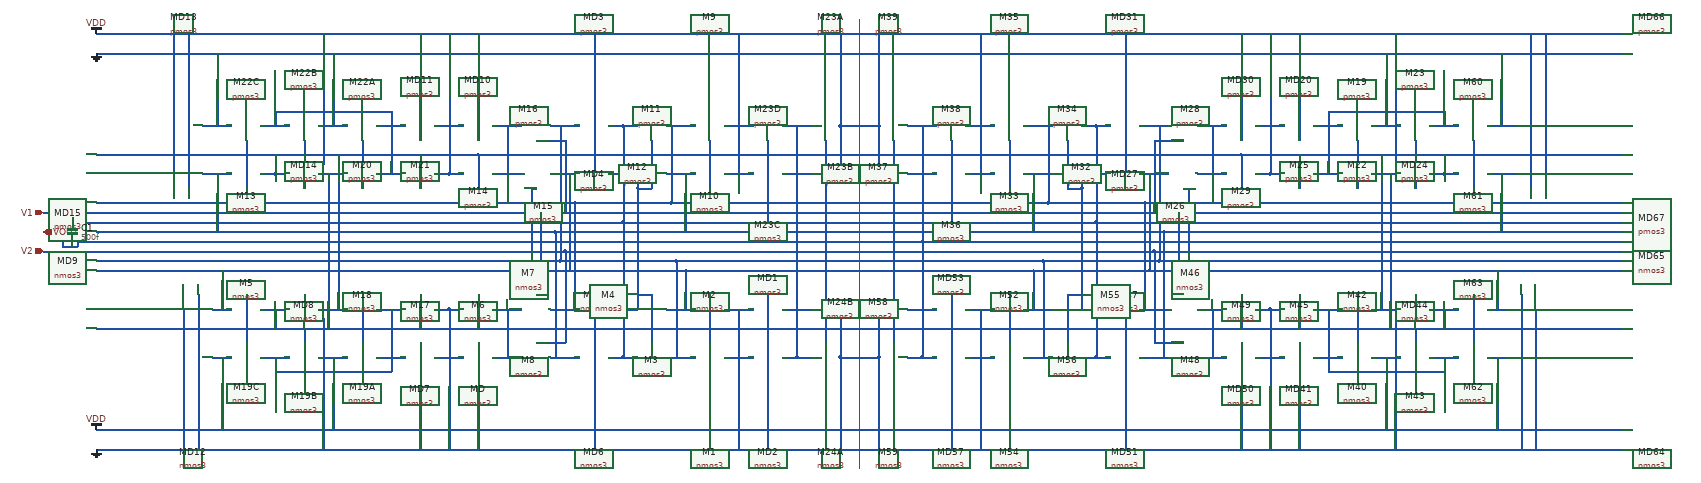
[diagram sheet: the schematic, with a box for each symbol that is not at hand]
v {xschem version=2.9.9 file_version=1.2 }
G {}
K {}
V {}
S {}
E {}
L 4 790 -520 790 410 {}
N -160 80 -150 80 { lab=#net1}
N 750 -300 750 -200 { lab=VDD}
N 630 -300 690 -300 { lab=VOUT}
N 600 -270 600 -170 { lab=#net2}
N 720 -270 720 -170 { lab=#net2}
N 660 -60 790 -60 { lab=VOUT}
N 660 80 690 80 { lab=VOUT}
N 660 180 690 180 { lab=VOUT}
N 750 80 750 180 { lab=GND}
N 720 50 720 150 { lab=#net2}
N 720 -170 720 50 { lab=#net2}
N 750 -490 750 -300 { lab=VDD}
N 540 -490 540 -200 { lab=VDD}
N 510 -200 570 -200 { lab=VDD}
N 510 -300 540 -300 { lab=VDD}
N 540 -300 570 -300 { lab=VDD}
N 390 -300 450 -300 { lab=#net3}
N 390 -200 450 -200 { lab=#net4}
N 360 -270 360 -170 { lab=#net5}
N 600 -170 600 -100 { lab=#net2}
N 300 -300 330 -300 { lab=#net2}
N 300 -300 300 -100 { lab=#net2}
N 300 -100 720 -100 { lab=#net2}
N 330 -200 330 -170 { lab=#net5}
N 330 -170 360 -170 { lab=#net5}
N 300 -100 300 180 { lab=#net2}
N 300 180 330 180 { lab=#net2}
N 510 80 570 80 { lab=GND}
N 540 80 540 370 { lab=GND}
N 330 -170 330 80 { lab=#net5}
N 330 50 360 50 { lab=#net5}
N 390 180 450 180 { lab=#net6}
N 390 80 450 80 { lab=#net7}
N 720 -100 790 -100 { lab=#net2}
N 270 180 300 180 { lab=#net2}
N 270 80 330 80 { lab=#net5}
N 270 -200 330 -200 { lab=#net5}
N 270 -300 300 -300 { lab=#net2}
N 480 50 480 150 { lab=#net8}
N 360 50 360 150 { lab=#net5}
N 630 80 660 80 { lab=VOUT}
N 630 180 660 180 { lab=VOUT}
N 510 180 540 180 { lab=GND}
N 540 180 570 180 { lab=GND}
N 180 -40 790 -40 { lab=V2}
N 120 150 180 150 { lab=V2}
N -790 -120 120 -120 { lab=#net9}
N -790 -40 180 -40 { lab=V2}
N 150 80 210 80 { lab=#net3}
N 150 180 210 180 { lab=#net4}
N 30 80 90 80 { lab=#net10}
N 30 180 90 180 { lab=#net10}
N 60 80 60 180 { lab=#net10}
N 660 -60 660 180 { lab=VOUT}
N 660 -300 660 -60 { lab=VOUT}
N 630 -200 660 -200 { lab=VOUT}
N 660 -200 690 -200 { lab=VOUT}
N 120 -120 790 -120 { lab=#net9}
N 200 -140 400 -140 { lab=#net3}
N 400 -300 400 -140 { lab=#net3}
N -790 -60 660 -60 { lab=VOUT}
N -790 -100 300 -100 { lab=#net2}
N 400 -140 790 -140 { lab=#net3}
N 160 -80 790 -80 { lab=#net4}
N -790 -80 160 -80 { lab=#net4}
N 430 -200 430 -80 { lab=#net4}
N 480 120 790 120 { lab=#net8}
N -790 120 480 120 { lab=#net8}
N 600 50 600 370 { lab=GND}
N 240 50 240 370 { lab=GND}
N 180 -40 180 150 { lab=V2}
N -90 180 -60 180 { lab=GND}
N -60 180 -30 180 { lab=GND}
N 0 50 0 120 { lab=#net8}
N -90 80 -60 80 { lab=GND}
N -60 80 -30 80 { lab=GND}
N -60 80 -60 370 { lab=GND}
N -120 50 -120 120 { lab=#net8}
N -210 80 -160 80 { lab=#net1}
N -180 80 -180 180 { lab=#net1}
N -210 180 -150 180 { lab=#net1}
N -240 120 -240 150 { lab=#net8}
N -240 50 -240 120 { lab=#net8}
N -330 180 -270 180 { lab=VDD}
N -550 180 -510 180 { lab=VDD}
N -450 180 -390 180 { lab=#net1}
N -480 120 -480 150 { lab=#net8}
N -360 120 -360 150 { lab=#net8}
N -330 80 -270 80 { lab=#net11}
N -450 80 -390 80 { lab=#net8}
N -420 80 -420 120 { lab=#net8}
N 150 -300 210 -300 { lab=#net6}
N 150 -200 210 -200 { lab=#net7}
N 410 -20 410 180 { lab=#net6}
N 170 -300 170 -20 { lab=#net6}
N 170 -20 410 -20 { lab=#net6}
N 410 -20 790 -20 { lab=#net6}
N -790 -20 170 -20 { lab=#net6}
N 430 0 430 80 { lab=#net7}
N 190 0 430 0 { lab=#net7}
N 190 -200 190 0 { lab=#net7}
N 180 -270 180 -120 { lab=#net9}
N 120 -270 180 -270 { lab=#net9}
N 130 -120 130 50 { lab=#net9}
N 120 50 130 50 { lab=#net9}
N 110 -170 110 -40 { lab=V2}
N 110 -170 120 -170 { lab=V2}
N 30 -300 90 -300 { lab=#net12}
N 30 -200 90 -200 { lab=#net12}
N 60 -300 60 -200 { lab=#net12}
N 0 -490 0 -270 { lab=VDD}
N 0 -240 0 -170 { lab=#net11}
N 0 -240 780 -240 { lab=#net11}
N 780 -240 790 -240 { lab=#net11}
N -790 -240 0 -240 { lab=#net11}
N -60 -200 -30 -200 { lab=VDD}
N -90 -200 -60 -200 { lab=VDD}
N -90 -300 -60 -300 { lab=VDD}
N -60 -300 -30 -300 { lab=VDD}
N -60 -490 -60 -200 { lab=VDD}
N -120 -490 -120 -270 { lab=VDD}
N -210 -200 -150 -200 { lab=#net13}
N -180 -300 -180 -200 { lab=#net13}
N -210 -300 -150 -300 { lab=#net13}
N -120 -240 -120 -170 { lab=#net11}
N -330 -300 -270 -300 { lab=GND}
N -240 -270 -240 -240 { lab=#net11}
N -360 -270 -360 -240 { lab=#net11}
N -450 -300 -390 -300 { lab=#net13}
N -300 180 -300 330 { lab=VDD}
N -180 180 -180 210 { lab=#net1}
N -420 210 -180 210 { lab=#net1}
N -420 180 -420 210 { lab=#net1}
N -530 180 -530 330 { lab=VDD}
N -550 80 -510 80 { lab=#net7}
N -300 -450 -300 -300 { lab=GND}
N -180 -330 -180 -300 { lab=#net13}
N -420 -330 -180 -330 { lab=#net13}
N -420 -330 -420 -300 { lab=#net13}
N -570 -300 -510 -300 { lab=GND}
N -540 -450 -540 -300 { lab=GND}
N -480 -270 -480 -240 { lab=#net11}
N -240 -240 -240 -170 { lab=#net11}
N -330 -200 -270 -200 { lab=#net8}
N -450 -200 -420 -200 { lab=#net11}
N -420 -200 -390 -200 { lab=#net11}
N -570 -200 -510 -200 { lab=#net4}
N -600 -490 -600 -170 { lab=VDD}
N -580 50 -580 370 { lab=GND}
N -790 0 190 0 { lab=#net7}
N 430 0 790 0 { lab=#net7}
N -530 0 -530 80 { lab=#net7}
N -610 80 -610 370 { lab=GND}
N -630 -490 -630 -200 { lab=VDD}
N 240 -490 240 -170 { lab=VDD}
N 750 180 750 370 { lab=GND}
N -360 50 -360 100 { lab=GND}
N 480 -270 480 -240 { lab=#net11}
N 480 -240 480 -170 { lab=#net11}
N -120 150 -120 370 { lab=GND}
N -0 150 -0 370 { lab=GND}
N -290 -240 -290 80 { lab=#net11}
N -480 -240 -480 -170 { lab=#net11}
N -420 -240 -420 -200 { lab=#net11}
N -360 -220 -360 -170 { lab=VDD}
N -360 -220 -320 -220 { lab=VDD}
N -320 -490 -320 -220 { lab=VDD}
N -360 100 -320 100 { lab=GND}
N -320 100 -320 370 { lab=GND}
N -310 -200 -310 120 { lab=#net8}
N -480 50 -480 120 { lab=#net8}
N 200 -140 200 80 { lab=#net3}
N 160 -80 160 180 { lab=#net4}
N -540 -200 -540 -80 { lab=#net4}
N -790 -140 200 -140 { lab=#net3}
N -830 -110 -830 -100 { lab=#net2}
N -840 -110 -830 -110 { lab=#net2}
N -830 -60 -830 -50 { lab=VOUT}
N -840 -50 -830 -50 { lab=VOUT}
N -850 -50 -840 -50 { lab=VOUT}
N 1730 80 1740 80 { lab=#net14}
N 830 -300 830 -200 { lab=VDD}
N 890 -300 950 -300 { lab=VOUT}
N 980 -270 980 -170 { lab=#net2}
N 860 -270 860 -170 { lab=#net2}
N 790 -60 920 -60 { lab=VOUT}
N 890 80 920 80 { lab=VOUT}
N 890 180 920 180 { lab=VOUT}
N 830 80 830 180 { lab=GND}
N 860 50 860 150 { lab=#net2}
N 860 -170 860 50 { lab=#net2}
N 830 -490 830 -300 { lab=VDD}
N 1040 -490 1040 -200 { lab=VDD}
N 1010 -200 1070 -200 { lab=VDD}
N 1040 -300 1070 -300 { lab=VDD}
N 1010 -300 1040 -300 { lab=VDD}
N 1130 -300 1190 -300 { lab=#net3}
N 1130 -200 1190 -200 { lab=#net4}
N 1220 -270 1220 -170 { lab=#net15}
N 980 -170 980 -100 { lab=#net2}
N 1250 -300 1280 -300 { lab=#net2}
N 1280 -300 1280 -100 { lab=#net2}
N 860 -100 1280 -100 { lab=#net2}
N 1250 -200 1250 -170 { lab=#net15}
N 1220 -170 1250 -170 { lab=#net15}
N 1280 -100 1280 180 { lab=#net2}
N 1250 180 1280 180 { lab=#net2}
N 1010 80 1070 80 { lab=GND}
N 1040 80 1040 370 { lab=GND}
N 1250 -170 1250 80 { lab=#net15}
N 1220 50 1250 50 { lab=#net15}
N 1130 180 1190 180 { lab=#net6}
N 1130 80 1190 80 { lab=#net7}
N 790 -100 860 -100 { lab=#net2}
N 1280 180 1310 180 { lab=#net2}
N 1250 80 1310 80 { lab=#net15}
N 1250 -200 1310 -200 { lab=#net15}
N 1280 -300 1310 -300 { lab=#net2}
N 1100 50 1100 150 { lab=#net8}
N 1220 50 1220 150 { lab=#net15}
N 920 80 950 80 { lab=VOUT}
N 920 180 950 180 { lab=VOUT}
N 1040 180 1070 180 { lab=GND}
N 1010 180 1040 180 { lab=GND}
N 790 -40 1400 -40 { lab=V2}
N 1400 150 1460 150 { lab=V2}
N 1460 -120 2370 -120 { lab=#net9}
N 1400 -40 2370 -40 { lab=V2}
N 1370 80 1430 80 { lab=#net3}
N 1370 180 1430 180 { lab=#net4}
N 1490 80 1550 80 { lab=#net16}
N 1490 180 1550 180 { lab=#net16}
N 1520 80 1520 180 { lab=#net16}
N 920 -60 920 180 { lab=VOUT}
N 920 -300 920 -60 { lab=VOUT}
N 920 -200 950 -200 { lab=VOUT}
N 890 -200 920 -200 { lab=VOUT}
N 790 -120 1460 -120 { lab=#net9}
N 1180 -140 1380 -140 { lab=#net3}
N 1180 -300 1180 -140 { lab=#net3}
N 920 -60 2370 -60 { lab=VOUT}
N 1280 -100 2370 -100 { lab=#net2}
N 790 -140 1180 -140 { lab=#net3}
N 790 -80 1420 -80 { lab=#net4}
N 1420 -80 2370 -80 { lab=#net4}
N 1150 -200 1150 -80 { lab=#net4}
N 790 120 1100 120 { lab=#net8}
N 1100 120 2370 120 { lab=#net8}
N 980 50 980 370 { lab=GND}
N 1340 50 1340 370 { lab=GND}
N 1400 -40 1400 150 { lab=V2}
N 1640 180 1670 180 { lab=GND}
N 1610 180 1640 180 { lab=GND}
N 1580 50 1580 120 { lab=#net8}
N 1640 80 1670 80 { lab=GND}
N 1610 80 1640 80 { lab=GND}
N 1640 80 1640 370 { lab=GND}
N 1700 50 1700 120 { lab=#net8}
N 1740 80 1790 80 { lab=#net14}
N 1760 80 1760 180 { lab=#net14}
N 1730 180 1790 180 { lab=#net14}
N 1820 120 1820 150 { lab=#net8}
N 1820 50 1820 120 { lab=#net8}
N 1850 180 1910 180 { lab=VDD}
N 2090 180 2130 180 { lab=VDD}
N 1970 180 2030 180 { lab=#net14}
N 2060 120 2060 150 { lab=#net8}
N 1940 120 1940 150 { lab=#net8}
N 1850 80 1910 80 { lab=#net11}
N 1970 80 2030 80 { lab=#net8}
N 2000 80 2000 120 { lab=#net8}
N 1370 -300 1430 -300 { lab=#net6}
N 1370 -200 1430 -200 { lab=#net7}
N 1170 -20 1170 180 { lab=#net6}
N 1410 -300 1410 -20 { lab=#net6}
N 1170 -20 1410 -20 { lab=#net6}
N 790 -20 1170 -20 { lab=#net6}
N 1410 -20 2370 -20 { lab=#net6}
N 1150 0 1150 80 { lab=#net7}
N 1150 0 1390 0 { lab=#net7}
N 1390 -200 1390 0 { lab=#net7}
N 1400 -270 1400 -120 { lab=#net9}
N 1400 -270 1460 -270 { lab=#net9}
N 1450 -120 1450 50 { lab=#net9}
N 1450 50 1460 50 { lab=#net9}
N 1470 -170 1470 -40 { lab=V2}
N 1460 -170 1470 -170 { lab=V2}
N 1490 -300 1550 -300 { lab=#net17}
N 1490 -200 1550 -200 { lab=#net17}
N 1520 -300 1520 -200 { lab=#net17}
N 1580 -490 1580 -270 { lab=VDD}
N 1580 -240 1580 -170 { lab=#net11}
N 800 -240 1580 -240 { lab=#net11}
N 790 -240 800 -240 { lab=#net11}
N 1580 -240 2370 -240 { lab=#net11}
N 1610 -200 1640 -200 { lab=VDD}
N 1640 -200 1670 -200 { lab=VDD}
N 1640 -300 1670 -300 { lab=VDD}
N 1610 -300 1640 -300 { lab=VDD}
N 1640 -490 1640 -200 { lab=VDD}
N 1700 -490 1700 -270 { lab=VDD}
N 1730 -200 1790 -200 { lab=#net18}
N 1760 -300 1760 -200 { lab=#net18}
N 1730 -300 1790 -300 { lab=#net18}
N 1700 -240 1700 -170 { lab=#net11}
N 1850 -300 1910 -300 { lab=GND}
N 1820 -270 1820 -240 { lab=#net11}
N 1940 -270 1940 -240 { lab=#net11}
N 1970 -300 2030 -300 { lab=#net18}
N 1880 180 1880 330 { lab=VDD}
N 1760 180 1760 210 { lab=#net14}
N 1760 210 2000 210 { lab=#net14}
N 2000 180 2000 210 { lab=#net14}
N 2110 180 2110 330 { lab=VDD}
N 2090 80 2130 80 { lab=#net7}
N 1880 -450 1880 -300 { lab=GND}
N 1760 -330 1760 -300 { lab=#net18}
N 1760 -330 2000 -330 { lab=#net18}
N 2000 -330 2000 -300 { lab=#net18}
N 2090 -300 2150 -300 { lab=GND}
N 2120 -450 2120 -300 { lab=GND}
N 2060 -270 2060 -240 { lab=#net11}
N 1820 -240 1820 -170 { lab=#net11}
N 1850 -200 1910 -200 { lab=#net8}
N 2000 -200 2030 -200 { lab=#net11}
N 1970 -200 2000 -200 { lab=#net11}
N 2090 -200 2150 -200 { lab=#net4}
N 2180 -490 2180 -170 { lab=VDD}
N 2160 50 2160 370 { lab=GND}
N 1390 0 2370 0 { lab=#net7}
N 790 0 1150 0 { lab=#net7}
N 2110 0 2110 80 { lab=#net7}
N 2190 80 2190 370 { lab=GND}
N 2210 -490 2210 -200 { lab=VDD}
N 1340 -490 1340 -170 { lab=VDD}
N 830 180 830 370 { lab=GND}
N 1940 50 1940 100 { lab=GND}
N 1100 -270 1100 -240 { lab=#net11}
N 1100 -240 1100 -170 { lab=#net11}
N 1700 150 1700 370 { lab=GND}
N 1580 150 1580 370 { lab=GND}
N 1870 -240 1870 80 { lab=#net11}
N 2060 -240 2060 -170 { lab=#net11}
N 2000 -240 2000 -200 { lab=#net11}
N 1940 -220 1940 -170 { lab=VDD}
N 1900 -220 1940 -220 { lab=VDD}
N 1900 -490 1900 -220 { lab=VDD}
N 1900 100 1940 100 { lab=GND}
N 1900 100 1900 370 { lab=GND}
N 1890 -200 1890 120 { lab=#net8}
N 2060 50 2060 120 { lab=#net8}
N 1380 -140 1380 80 { lab=#net3}
N 1420 -80 1420 180 { lab=#net4}
N 2120 -200 2120 -80 { lab=#net4}
N 1380 -140 2370 -140 { lab=#net3}
N 790 -450 2370 -450 { lab=GND}
N 790 -490 2370 -490 { lab=VDD}
N 790 330 2370 330 { lab=VDD}
N 790 370 2370 370 { lab=GND}
N -790 330 790 330 { lab=VDD}
N -790 370 790 370 { lab=GND}
N -790 -490 790 -490 { lab=VDD}
N -790 -450 790 -450 { lab=GND}
N 750 -300 830 -300 { lab=VDD}
N 750 -200 830 -200 { lab=VDD}
N 750 180 830 180 { lab=GND}
N 750 80 830 80 { lab=GND}
N -830 -100 -790 -100 { lab=#net2}
N -830 -60 -790 -60 { lab=VOUT}
N -860 -50 -850 -50 { lab=VOUT}
N -860 -80 -860 -50 { lab=VOUT}
N -900 -80 -860 -80 { lab=VOUT}
N -900 -40 -790 -40 {}
N -900 -120 -790 -120 {}
C {madvlsi/pmos3.sym} -240 -300 3 0 {name=M22A
L=.6
W=1.5
body=VDD
nf=1
mult=1
ad="'int((nf+1)/2) * W/nf * 0.29'" 
pd="'2*int((nf+1)/2) * (W/nf + 0.29)'"
as="'int((nf+2)/2) * W/nf * 0.29'" 
ps="'2*int((nf+2)/2) * (W/nf + 0.29)'"
nrd="'0.29 / W'" nrs="'0.29 / W'"
sa=0 sb=0 sd=0
model=pfet_01v8
spiceprefix=X
}
C {madvlsi/pmos3.sym} -120 -300 3 0 {name=MD11
L=.6
W=1.5
body=VDD
nf=1
mult=1
ad="'int((nf+1)/2) * W/nf * 0.29'" 
pd="'2*int((nf+1)/2) * (W/nf + 0.29)'"
as="'int((nf+2)/2) * W/nf * 0.29'" 
ps="'2*int((nf+2)/2) * (W/nf + 0.29)'"
nrd="'0.29 / W'" nrs="'0.29 / W'"
sa=0 sb=0 sd=0
model=pfet_01v8
spiceprefix=X
}
C {madvlsi/pmos3.sym} -240 -200 3 0 {name=M20
L=.6
W=1.5
body=VDD
nf=1
mult=1
ad="'int((nf+1)/2) * W/nf * 0.29'" 
pd="'2*int((nf+1)/2) * (W/nf + 0.29)'"
as="'int((nf+2)/2) * W/nf * 0.29'" 
ps="'2*int((nf+2)/2) * (W/nf + 0.29)'"
nrd="'0.29 / W'" nrs="'0.29 / W'"
sa=0 sb=0 sd=0
model=pfet_01v8
spiceprefix=X
}
C {madvlsi/pmos3.sym} -360 -300 3 0 {name=M22B
L=.6
W=1.5
body=VDD
nf=1
mult=1
ad="'int((nf+1)/2) * W/nf * 0.29'" 
pd="'2*int((nf+1)/2) * (W/nf + 0.29)'"
as="'int((nf+2)/2) * W/nf * 0.29'" 
ps="'2*int((nf+2)/2) * (W/nf + 0.29)'"
nrd="'0.29 / W'" nrs="'0.29 / W'"
sa=0 sb=0 sd=0
model=pfet_01v8
spiceprefix=X
}
C {madvlsi/pmos3.sym} -360 -200 3 0 {name=MD14
L=.6
W=1.5
body=VDD
nf=1
mult=1
ad="'int((nf+1)/2) * W/nf * 0.29'" 
pd="'2*int((nf+1)/2) * (W/nf + 0.29)'"
as="'int((nf+2)/2) * W/nf * 0.29'" 
ps="'2*int((nf+2)/2) * (W/nf + 0.29)'"
nrd="'0.29 / W'" nrs="'0.29 / W'"
sa=0 sb=0 sd=0
model=pfet_01v8
spiceprefix=X
}
C {madvlsi/pmos3.sym} -120 -200 3 0 {name=M21
L=.6
W=1.5
body=VDD
nf=1
mult=1
ad="'int((nf+1)/2) * W/nf * 0.29'" 
pd="'2*int((nf+1)/2) * (W/nf + 0.29)'"
as="'int((nf+2)/2) * W/nf * 0.29'" 
ps="'2*int((nf+2)/2) * (W/nf + 0.29)'"
nrd="'0.29 / W'" nrs="'0.29 / W'"
sa=0 sb=0 sd=0
model=pfet_01v8
spiceprefix=X
}
C {madvlsi/pmos3.sym} 120 -200 3 0 {name=M15
L=.6
W=1.5
body=VDD
nf=1
mult=1
ad="'int((nf+1)/2) * W/nf * 0.29'" 
pd="'2*int((nf+1)/2) * (W/nf + 0.29)'"
as="'int((nf+2)/2) * W/nf * 0.29'" 
ps="'2*int((nf+2)/2) * (W/nf + 0.29)'"
nrd="'0.29 / W'" nrs="'0.29 / W'"
sa=0 sb=0 sd=0
model=pfet_01v8
spiceprefix=X
}
C {madvlsi/pmos3.sym} 240 -200 3 0 {name=MD4
L=.6
W=1.5
body=VDD
nf=1
mult=1
ad="'int((nf+1)/2) * W/nf * 0.29'" 
pd="'2*int((nf+1)/2) * (W/nf + 0.29)'"
as="'int((nf+2)/2) * W/nf * 0.29'" 
ps="'2*int((nf+2)/2) * (W/nf + 0.29)'"
nrd="'0.29 / W'" nrs="'0.29 / W'"
sa=0 sb=0 sd=0
model=pfet_01v8
spiceprefix=X
}
C {madvlsi/pmos3.sym} 120 -300 3 0 {name=M16
L=.6
W=1.5
body=VDD
nf=1
mult=1
ad="'int((nf+1)/2) * W/nf * 0.29'" 
pd="'2*int((nf+1)/2) * (W/nf + 0.29)'"
as="'int((nf+2)/2) * W/nf * 0.29'" 
ps="'2*int((nf+2)/2) * (W/nf + 0.29)'"
nrd="'0.29 / W'" nrs="'0.29 / W'"
sa=0 sb=0 sd=0
model=pfet_01v8
spiceprefix=X
}
C {madvlsi/pmos3.sym} 0 -200 3 0 {name=M14
L=.6
W=1.5
body=VDD
nf=1
mult=1
ad="'int((nf+1)/2) * W/nf * 0.29'" 
pd="'2*int((nf+1)/2) * (W/nf + 0.29)'"
as="'int((nf+2)/2) * W/nf * 0.29'" 
ps="'2*int((nf+2)/2) * (W/nf + 0.29)'"
nrd="'0.29 / W'" nrs="'0.29 / W'"
sa=0 sb=0 sd=0
model=pfet_01v8
spiceprefix=X
}
C {madvlsi/pmos3.sym} 0 -300 3 0 {name=MD10
L=.6
W=1.5
body=VDD
nf=1
mult=1
ad="'int((nf+1)/2) * W/nf * 0.29'" 
pd="'2*int((nf+1)/2) * (W/nf + 0.29)'"
as="'int((nf+2)/2) * W/nf * 0.29'" 
ps="'2*int((nf+2)/2) * (W/nf + 0.29)'"
nrd="'0.29 / W'" nrs="'0.29 / W'"
sa=0 sb=0 sd=0
model=pfet_01v8
spiceprefix=X
}
C {madvlsi/pmos3.sym} 240 -300 3 0 {name=MD3
L=.6
W=1.5
body=VDD
nf=1
mult=1
ad="'int((nf+1)/2) * W/nf * 0.29'" 
pd="'2*int((nf+1)/2) * (W/nf + 0.29)'"
as="'int((nf+2)/2) * W/nf * 0.29'" 
ps="'2*int((nf+2)/2) * (W/nf + 0.29)'"
nrd="'0.29 / W'" nrs="'0.29 / W'"
sa=0 sb=0 sd=0
model=pfet_01v8
spiceprefix=X
}
C {madvlsi/pmos3.sym} 360 -200 3 0 {name=M12
L=.6
W=1.5
body=VDD
nf=1
mult=1
ad="'int((nf+1)/2) * W/nf * 0.29'" 
pd="'2*int((nf+1)/2) * (W/nf + 0.29)'"
as="'int((nf+2)/2) * W/nf * 0.29'" 
ps="'2*int((nf+2)/2) * (W/nf + 0.29)'"
nrd="'0.29 / W'" nrs="'0.29 / W'"
sa=0 sb=0 sd=0
model=pfet_01v8
spiceprefix=X
}
C {madvlsi/pmos3.sym} 480 -200 3 0 {name=M10
L=.6
W=1.5
body=VDD
nf=1
mult=1
ad="'int((nf+1)/2) * W/nf * 0.29'" 
pd="'2*int((nf+1)/2) * (W/nf + 0.29)'"
as="'int((nf+2)/2) * W/nf * 0.29'" 
ps="'2*int((nf+2)/2) * (W/nf + 0.29)'"
nrd="'0.29 / W'" nrs="'0.29 / W'"
sa=0 sb=0 sd=0
model=pfet_01v8
spiceprefix=X
}
C {madvlsi/pmos3.sym} 360 -300 3 0 {name=M11
L=.6
W=1.5
body=VDD
nf=1
mult=1
ad="'int((nf+1)/2) * W/nf * 0.29'" 
pd="'2*int((nf+1)/2) * (W/nf + 0.29)'"
as="'int((nf+2)/2) * W/nf * 0.29'" 
ps="'2*int((nf+2)/2) * (W/nf + 0.29)'"
nrd="'0.29 / W'" nrs="'0.29 / W'"
sa=0 sb=0 sd=0
model=pfet_01v8
spiceprefix=X
}
C {madvlsi/pmos3.sym} 480 -300 3 0 {name=M9
L=.6
W=1.5
body=VDD
nf=1
mult=1
ad="'int((nf+1)/2) * W/nf * 0.29'" 
pd="'2*int((nf+1)/2) * (W/nf + 0.29)'"
as="'int((nf+2)/2) * W/nf * 0.29'" 
ps="'2*int((nf+2)/2) * (W/nf + 0.29)'"
nrd="'0.29 / W'" nrs="'0.29 / W'"
sa=0 sb=0 sd=0
model=pfet_01v8
spiceprefix=X
}
C {madvlsi/pmos3.sym} 600 -200 3 0 {name=M23C
L=.6
W=1.5
body=VDD
nf=1
mult=1
ad="'int((nf+1)/2) * W/nf * 0.29'" 
pd="'2*int((nf+1)/2) * (W/nf + 0.29)'"
as="'int((nf+2)/2) * W/nf * 0.29'" 
ps="'2*int((nf+2)/2) * (W/nf + 0.29)'"
nrd="'0.29 / W'" nrs="'0.29 / W'"
sa=0 sb=0 sd=0
model=pfet_01v8
spiceprefix=X
}
C {madvlsi/pmos3.sym} 720 -200 3 0 {name=M23B
L=.6
W=1.5
body=VDD
nf=1
mult=1
ad="'int((nf+1)/2) * W/nf * 0.29'" 
pd="'2*int((nf+1)/2) * (W/nf + 0.29)'"
as="'int((nf+2)/2) * W/nf * 0.29'" 
ps="'2*int((nf+2)/2) * (W/nf + 0.29)'"
nrd="'0.29 / W'" nrs="'0.29 / W'"
sa=0 sb=0 sd=0
model=pfet_01v8
spiceprefix=X
}
C {madvlsi/pmos3.sym} 600 -300 3 0 {name=M23D
L=.6
W=1.5
body=VDD
nf=1
mult=1
ad="'int((nf+1)/2) * W/nf * 0.29'" 
pd="'2*int((nf+1)/2) * (W/nf + 0.29)'"
as="'int((nf+2)/2) * W/nf * 0.29'" 
ps="'2*int((nf+2)/2) * (W/nf + 0.29)'"
nrd="'0.29 / W'" nrs="'0.29 / W'"
sa=0 sb=0 sd=0
model=pfet_01v8
spiceprefix=X
}
C {madvlsi/pmos3.sym} 720 -300 3 0 {name=M23A
L=.6
W=1.5
body=VDD
nf=1
mult=1
ad="'int((nf+1)/2) * W/nf * 0.29'" 
pd="'2*int((nf+1)/2) * (W/nf + 0.29)'"
as="'int((nf+2)/2) * W/nf * 0.29'" 
ps="'2*int((nf+2)/2) * (W/nf + 0.29)'"
nrd="'0.29 / W'" nrs="'0.29 / W'"
sa=0 sb=0 sd=0
model=pfet_01v8
spiceprefix=X
}
C {madvlsi/nmos3.sym} -240 180 1 0 {name=M19A
L=.6
W=1.5
body=GND
nf=1
mult=1
ad="'int((nf+1)/2) * W/nf * 0.29'" 
pd="'2*int((nf+1)/2) * (W/nf + 0.29)'"
as="'int((nf+2)/2) * W/nf * 0.29'" 
ps="'2*int((nf+2)/2) * (W/nf + 0.29)'"
nrd="'0.29 / W'" nrs="'0.29 / W'"
sa=0 sb=0 sd=0
model=nfet_01v8
spiceprefix=X
}
C {madvlsi/nmos3.sym} -120 180 1 0 {name=MD7
L=.6
W=1.5
body=GND
nf=1
mult=1
ad="'int((nf+1)/2) * W/nf * 0.29'" 
pd="'2*int((nf+1)/2) * (W/nf + 0.29)'"
as="'int((nf+2)/2) * W/nf * 0.29'" 
ps="'2*int((nf+2)/2) * (W/nf + 0.29)'"
nrd="'0.29 / W'" nrs="'0.29 / W'"
sa=0 sb=0 sd=0
model=nfet_01v8
spiceprefix=X
}
C {madvlsi/nmos3.sym} -240 80 1 0 {name=M18
L=.6
W=1.5
body=GND
nf=1
mult=1
ad="'int((nf+1)/2) * W/nf * 0.29'" 
pd="'2*int((nf+1)/2) * (W/nf + 0.29)'"
as="'int((nf+2)/2) * W/nf * 0.29'" 
ps="'2*int((nf+2)/2) * (W/nf + 0.29)'"
nrd="'0.29 / W'" nrs="'0.29 / W'"
sa=0 sb=0 sd=0
model=nfet_01v8
spiceprefix=X
}
C {madvlsi/nmos3.sym} -360 180 1 0 {name=M19B
L=.6
W=1.5
body=GND
nf=1
mult=1
ad="'int((nf+1)/2) * W/nf * 0.29'" 
pd="'2*int((nf+1)/2) * (W/nf + 0.29)'"
as="'int((nf+2)/2) * W/nf * 0.29'" 
ps="'2*int((nf+2)/2) * (W/nf + 0.29)'"
nrd="'0.29 / W'" nrs="'0.29 / W'"
sa=0 sb=0 sd=0
model=nfet_01v8
spiceprefix=X
}
C {madvlsi/nmos3.sym} -360 80 1 0 {name=MD8
L=.6
W=1.5
body=GND
nf=1
mult=1
ad="'int((nf+1)/2) * W/nf * 0.29'" 
pd="'2*int((nf+1)/2) * (W/nf + 0.29)'"
as="'int((nf+2)/2) * W/nf * 0.29'" 
ps="'2*int((nf+2)/2) * (W/nf + 0.29)'"
nrd="'0.29 / W'" nrs="'0.29 / W'"
sa=0 sb=0 sd=0
model=nfet_01v8
spiceprefix=X
}
C {madvlsi/nmos3.sym} -120 80 1 0 {name=M17
L=.6
W=1.5
body=GND
nf=1
mult=1
ad="'int((nf+1)/2) * W/nf * 0.29'" 
pd="'2*int((nf+1)/2) * (W/nf + 0.29)'"
as="'int((nf+2)/2) * W/nf * 0.29'" 
ps="'2*int((nf+2)/2) * (W/nf + 0.29)'"
nrd="'0.29 / W'" nrs="'0.29 / W'"
sa=0 sb=0 sd=0
model=nfet_01v8
spiceprefix=X
}
C {madvlsi/nmos3.sym} 120 80 1 0 {name=M7
L=.6
W=1.5
body=GND
nf=1
mult=1
ad="'int((nf+1)/2) * W/nf * 0.29'" 
pd="'2*int((nf+1)/2) * (W/nf + 0.29)'"
as="'int((nf+2)/2) * W/nf * 0.29'" 
ps="'2*int((nf+2)/2) * (W/nf + 0.29)'"
nrd="'0.29 / W'" nrs="'0.29 / W'"
sa=0 sb=0 sd=0
model=nfet_01v8
spiceprefix=X
}
C {madvlsi/nmos3.sym} 240 80 1 0 {name=MD5
L=.6
W=1.5
body=GND
nf=1
mult=1
ad="'int((nf+1)/2) * W/nf * 0.29'" 
pd="'2*int((nf+1)/2) * (W/nf + 0.29)'"
as="'int((nf+2)/2) * W/nf * 0.29'" 
ps="'2*int((nf+2)/2) * (W/nf + 0.29)'"
nrd="'0.29 / W'" nrs="'0.29 / W'"
sa=0 sb=0 sd=0
model=nfet_01v8
spiceprefix=X
}
C {madvlsi/nmos3.sym} 120 180 1 0 {name=M8
L=.6
W=1.5
body=GND
nf=1
mult=1
ad="'int((nf+1)/2) * W/nf * 0.29'" 
pd="'2*int((nf+1)/2) * (W/nf + 0.29)'"
as="'int((nf+2)/2) * W/nf * 0.29'" 
ps="'2*int((nf+2)/2) * (W/nf + 0.29)'"
nrd="'0.29 / W'" nrs="'0.29 / W'"
sa=0 sb=0 sd=0
model=nfet_01v8
spiceprefix=X
}
C {madvlsi/nmos3.sym} 0 80 1 0 {name=M6
L=.6
W=1.5
body=GND
nf=1
mult=1
ad="'int((nf+1)/2) * W/nf * 0.29'" 
pd="'2*int((nf+1)/2) * (W/nf + 0.29)'"
as="'int((nf+2)/2) * W/nf * 0.29'" 
ps="'2*int((nf+2)/2) * (W/nf + 0.29)'"
nrd="'0.29 / W'" nrs="'0.29 / W'"
sa=0 sb=0 sd=0
model=nfet_01v8
spiceprefix=X
}
C {madvlsi/nmos3.sym} 0 180 1 0 {name=MD
L=.6
W=1.5
body=GND
nf=1
mult=1
ad="'int((nf+1)/2) * W/nf * 0.29'" 
pd="'2*int((nf+1)/2) * (W/nf + 0.29)'"
as="'int((nf+2)/2) * W/nf * 0.29'" 
ps="'2*int((nf+2)/2) * (W/nf + 0.29)'"
nrd="'0.29 / W'" nrs="'0.29 / W'"
sa=0 sb=0 sd=0
model=nfet_01v8
spiceprefix=X
}
C {madvlsi/nmos3.sym} 240 180 1 0 {name=MD6
L=.6
W=1.5
body=GND
nf=1
mult=1
ad="'int((nf+1)/2) * W/nf * 0.29'" 
pd="'2*int((nf+1)/2) * (W/nf + 0.29)'"
as="'int((nf+2)/2) * W/nf * 0.29'" 
ps="'2*int((nf+2)/2) * (W/nf + 0.29)'"
nrd="'0.29 / W'" nrs="'0.29 / W'"
sa=0 sb=0 sd=0
model=nfet_01v8
spiceprefix=X
}
C {madvlsi/nmos3.sym} 480 80 1 0 {name=M2
L=.6
W=1.5
body=GND
nf=1
mult=1
ad="'int((nf+1)/2) * W/nf * 0.29'" 
pd="'2*int((nf+1)/2) * (W/nf + 0.29)'"
as="'int((nf+2)/2) * W/nf * 0.29'" 
ps="'2*int((nf+2)/2) * (W/nf + 0.29)'"
nrd="'0.29 / W'" nrs="'0.29 / W'"
sa=0 sb=0 sd=0
model=nfet_01v8
spiceprefix=X
}
C {madvlsi/nmos3.sym} 600 80 1 0 {name=MD1
L=.6
W=1.5
body=GND
nf=1
mult=1
ad="'int((nf+1)/2) * W/nf * 0.29'" 
pd="'2*int((nf+1)/2) * (W/nf + 0.29)'"
as="'int((nf+2)/2) * W/nf * 0.29'" 
ps="'2*int((nf+2)/2) * (W/nf + 0.29)'"
nrd="'0.29 / W'" nrs="'0.29 / W'"
sa=0 sb=0 sd=0
model=nfet_01v8
spiceprefix=X
}
C {madvlsi/nmos3.sym} 480 180 1 0 {name=M1
L=.6
W=1.5
body=GND
nf=1
mult=1
ad="'int((nf+1)/2) * W/nf * 0.29'" 
pd="'2*int((nf+1)/2) * (W/nf + 0.29)'"
as="'int((nf+2)/2) * W/nf * 0.29'" 
ps="'2*int((nf+2)/2) * (W/nf + 0.29)'"
nrd="'0.29 / W'" nrs="'0.29 / W'"
sa=0 sb=0 sd=0
model=nfet_01v8
spiceprefix=X
}
C {madvlsi/nmos3.sym} 360 80 1 0 {name=M4
L=.6
W=1.5
body=GND
nf=1
mult=1
ad="'int((nf+1)/2) * W/nf * 0.29'" 
pd="'2*int((nf+1)/2) * (W/nf + 0.29)'"
as="'int((nf+2)/2) * W/nf * 0.29'" 
ps="'2*int((nf+2)/2) * (W/nf + 0.29)'"
nrd="'0.29 / W'" nrs="'0.29 / W'"
sa=0 sb=0 sd=0
model=nfet_01v8
spiceprefix=X
}
C {madvlsi/nmos3.sym} 360 180 1 0 {name=M3
L=.6
W=1.5
body=GND
nf=1
mult=1
ad="'int((nf+1)/2) * W/nf * 0.29'" 
pd="'2*int((nf+1)/2) * (W/nf + 0.29)'"
as="'int((nf+2)/2) * W/nf * 0.29'" 
ps="'2*int((nf+2)/2) * (W/nf + 0.29)'"
nrd="'0.29 / W'" nrs="'0.29 / W'"
sa=0 sb=0 sd=0
model=nfet_01v8
spiceprefix=X
}
C {madvlsi/nmos3.sym} 600 180 1 0 {name=MD2
L=.6
W=1.5
body=GND
nf=1
mult=1
ad="'int((nf+1)/2) * W/nf * 0.29'" 
pd="'2*int((nf+1)/2) * (W/nf + 0.29)'"
as="'int((nf+2)/2) * W/nf * 0.29'" 
ps="'2*int((nf+2)/2) * (W/nf + 0.29)'"
nrd="'0.29 / W'" nrs="'0.29 / W'"
sa=0 sb=0 sd=0
model=nfet_01v8
spiceprefix=X
}
C {madvlsi/nmos3.sym} 720 80 1 0 {name=M24B
L=.6
W=1.5
body=GND
nf=1
mult=1
ad="'int((nf+1)/2) * W/nf * 0.29'" 
pd="'2*int((nf+1)/2) * (W/nf + 0.29)'"
as="'int((nf+2)/2) * W/nf * 0.29'" 
ps="'2*int((nf+2)/2) * (W/nf + 0.29)'"
nrd="'0.29 / W'" nrs="'0.29 / W'"
sa=0 sb=0 sd=0
model=nfet_01v8
spiceprefix=X
}
C {madvlsi/nmos3.sym} 720 180 1 0 {name=M24A
L=.6
W=1.5
body=GND
nf=1
mult=1
ad="'int((nf+1)/2) * W/nf * 0.29'" 
pd="'2*int((nf+1)/2) * (W/nf + 0.29)'"
as="'int((nf+2)/2) * W/nf * 0.29'" 
ps="'2*int((nf+2)/2) * (W/nf + 0.29)'"
nrd="'0.29 / W'" nrs="'0.29 / W'"
sa=0 sb=0 sd=0
model=nfet_01v8
spiceprefix=X
}
C {madvlsi/pmos3.sym} -480 -300 3 0 {name=M22C
L=.6
W=1.5
body=VDD
nf=1
mult=1
ad="'int((nf+1)/2) * W/nf * 0.29'" 
pd="'2*int((nf+1)/2) * (W/nf + 0.29)'"
as="'int((nf+2)/2) * W/nf * 0.29'" 
ps="'2*int((nf+2)/2) * (W/nf + 0.29)'"
nrd="'0.29 / W'" nrs="'0.29 / W'"
sa=0 sb=0 sd=0
model=pfet_01v8
spiceprefix=X
}
C {madvlsi/pmos3.sym} -480 -200 3 0 {name=M13
L=.6
W=1.5
body=VDD
nf=1
mult=1
ad="'int((nf+1)/2) * W/nf * 0.29'" 
pd="'2*int((nf+1)/2) * (W/nf + 0.29)'"
as="'int((nf+2)/2) * W/nf * 0.29'" 
ps="'2*int((nf+2)/2) * (W/nf + 0.29)'"
nrd="'0.29 / W'" nrs="'0.29 / W'"
sa=0 sb=0 sd=0
model=pfet_01v8
spiceprefix=X
}
C {madvlsi/nmos3.sym} -480 180 1 0 {name=M19C
L=.6
W=1.5
body=GND
nf=1
mult=1
ad="'int((nf+1)/2) * W/nf * 0.29'" 
pd="'2*int((nf+1)/2) * (W/nf + 0.29)'"
as="'int((nf+2)/2) * W/nf * 0.29'" 
ps="'2*int((nf+2)/2) * (W/nf + 0.29)'"
nrd="'0.29 / W'" nrs="'0.29 / W'"
sa=0 sb=0 sd=0
model=nfet_01v8
spiceprefix=X
}
C {madvlsi/nmos3.sym} -480 80 1 0 {name=M5
L=.6
W=1.5
body=GND
nf=1
mult=1
ad="'int((nf+1)/2) * W/nf * 0.29'" 
pd="'2*int((nf+1)/2) * (W/nf + 0.29)'"
as="'int((nf+2)/2) * W/nf * 0.29'" 
ps="'2*int((nf+2)/2) * (W/nf + 0.29)'"
nrd="'0.29 / W'" nrs="'0.29 / W'"
sa=0 sb=0 sd=0
model=nfet_01v8
spiceprefix=X
}
C {madvlsi/nmos3.sym} -580 180 1 0 {name=MD12
L=.6
W=1.5
body=GND
nf=1
mult=1
ad="'int((nf+1)/2) * W/nf * 0.29'" 
pd="'2*int((nf+1)/2) * (W/nf + 0.29)'"
as="'int((nf+2)/2) * W/nf * 0.29'" 
ps="'2*int((nf+2)/2) * (W/nf + 0.29)'"
nrd="'0.29 / W'" nrs="'0.29 / W'"
sa=0 sb=0 sd=0
model=nfet_01v8
spiceprefix=X
}
C {madvlsi/nmos3.sym} -580 80 1 0 {name=MD9
L=.6
W=1.5
body=GND
nf=1
mult=1
ad="'int((nf+1)/2) * W/nf * 0.29'" 
pd="'2*int((nf+1)/2) * (W/nf + 0.29)'"
as="'int((nf+2)/2) * W/nf * 0.29'" 
ps="'2*int((nf+2)/2) * (W/nf + 0.29)'"
nrd="'0.29 / W'" nrs="'0.29 / W'"
sa=0 sb=0 sd=0
model=nfet_01v8
spiceprefix=X
}
C {madvlsi/pmos3.sym} -600 -300 3 0 {name=MD13
L=.6
W=1.5
body=VDD
nf=1
mult=1
ad="'int((nf+1)/2) * W/nf * 0.29'" 
pd="'2*int((nf+1)/2) * (W/nf + 0.29)'"
as="'int((nf+2)/2) * W/nf * 0.29'" 
ps="'2*int((nf+2)/2) * (W/nf + 0.29)'"
nrd="'0.29 / W'" nrs="'0.29 / W'"
sa=0 sb=0 sd=0
model=pfet_01v8
spiceprefix=X
}
C {madvlsi/pmos3.sym} -600 -200 3 0 {name=MD15
L=.6
W=1.5
body=VDD
nf=1
mult=1
ad="'int((nf+1)/2) * W/nf * 0.29'" 
pd="'2*int((nf+1)/2) * (W/nf + 0.29)'"
as="'int((nf+2)/2) * W/nf * 0.29'" 
ps="'2*int((nf+2)/2) * (W/nf + 0.29)'"
nrd="'0.29 / W'" nrs="'0.29 / W'"
sa=0 sb=0 sd=0
model=pfet_01v8
spiceprefix=X
}
C {madvlsi/gnd.sym} -790 370 0 0 {name=l1 lab=GND}
C {madvlsi/vdd.sym} -790 330 0 0 {name=l2 lab=VDD}
C {madvlsi/gnd.sym} -790 -450 0 0 {name=l3 lab=GND}
C {madvlsi/vdd.sym} -790 -490 0 0 {name=l4 lab=VDD}
C {devices/ipin.sym} -900 -120 0 0 {name=p1 lab=V1}
C {devices/ipin.sym} -900 -40 0 0 {name=p2 lab=V2}
C {devices/opin.sym} -900 -80 2 0 {name=p3 lab=VOUT}
C {madvlsi/capacitor.sym} -840 -80 0 0 {name=C1
value=500f
m=1}
C {madvlsi/pmos3.sym} 1820 -300 1 1 {name=M19
L=.6
W=1.5
body=VDD
nf=1
mult=1
ad="'int((nf+1)/2) * W/nf * 0.29'" 
pd="'2*int((nf+1)/2) * (W/nf + 0.29)'"
as="'int((nf+2)/2) * W/nf * 0.29'" 
ps="'2*int((nf+2)/2) * (W/nf + 0.29)'"
nrd="'0.29 / W'" nrs="'0.29 / W'"
sa=0 sb=0 sd=0
model=pfet_01v8
spiceprefix=X
}
C {madvlsi/pmos3.sym} 1700 -300 1 1 {name=MD20
L=.6
W=1.5
body=VDD
nf=1
mult=1
ad="'int((nf+1)/2) * W/nf * 0.29'" 
pd="'2*int((nf+1)/2) * (W/nf + 0.29)'"
as="'int((nf+2)/2) * W/nf * 0.29'" 
ps="'2*int((nf+2)/2) * (W/nf + 0.29)'"
nrd="'0.29 / W'" nrs="'0.29 / W'"
sa=0 sb=0 sd=0
model=pfet_01v8
spiceprefix=X
}
C {madvlsi/pmos3.sym} 1820 -200 1 1 {name=M22
L=.6
W=1.5
body=VDD
nf=1
mult=1
ad="'int((nf+1)/2) * W/nf * 0.29'" 
pd="'2*int((nf+1)/2) * (W/nf + 0.29)'"
as="'int((nf+2)/2) * W/nf * 0.29'" 
ps="'2*int((nf+2)/2) * (W/nf + 0.29)'"
nrd="'0.29 / W'" nrs="'0.29 / W'"
sa=0 sb=0 sd=0
model=pfet_01v8
spiceprefix=X
}
C {madvlsi/pmos3.sym} 1940 -300 1 1 {name=M23
L=.6
W=1.5
body=VDD
nf=1
mult=1
ad="'int((nf+1)/2) * W/nf * 0.29'" 
pd="'2*int((nf+1)/2) * (W/nf + 0.29)'"
as="'int((nf+2)/2) * W/nf * 0.29'" 
ps="'2*int((nf+2)/2) * (W/nf + 0.29)'"
nrd="'0.29 / W'" nrs="'0.29 / W'"
sa=0 sb=0 sd=0
model=pfet_01v8
spiceprefix=X
}
C {madvlsi/pmos3.sym} 1940 -200 1 1 {name=MD24
L=.6
W=1.5
body=VDD
nf=1
mult=1
ad="'int((nf+1)/2) * W/nf * 0.29'" 
pd="'2*int((nf+1)/2) * (W/nf + 0.29)'"
as="'int((nf+2)/2) * W/nf * 0.29'" 
ps="'2*int((nf+2)/2) * (W/nf + 0.29)'"
nrd="'0.29 / W'" nrs="'0.29 / W'"
sa=0 sb=0 sd=0
model=pfet_01v8
spiceprefix=X
}
C {madvlsi/pmos3.sym} 1700 -200 1 1 {name=M25
L=.6
W=1.5
body=VDD
nf=1
mult=1
ad="'int((nf+1)/2) * W/nf * 0.29'" 
pd="'2*int((nf+1)/2) * (W/nf + 0.29)'"
as="'int((nf+2)/2) * W/nf * 0.29'" 
ps="'2*int((nf+2)/2) * (W/nf + 0.29)'"
nrd="'0.29 / W'" nrs="'0.29 / W'"
sa=0 sb=0 sd=0
model=pfet_01v8
spiceprefix=X
}
C {madvlsi/pmos3.sym} 1460 -200 1 1 {name=M26
L=.6
W=1.5
body=VDD
nf=1
mult=1
ad="'int((nf+1)/2) * W/nf * 0.29'" 
pd="'2*int((nf+1)/2) * (W/nf + 0.29)'"
as="'int((nf+2)/2) * W/nf * 0.29'" 
ps="'2*int((nf+2)/2) * (W/nf + 0.29)'"
nrd="'0.29 / W'" nrs="'0.29 / W'"
sa=0 sb=0 sd=0
model=pfet_01v8
spiceprefix=X
}
C {madvlsi/pmos3.sym} 1340 -200 1 1 {name=MD27
L=.6
W=1.5
body=VDD
nf=1
mult=1
ad="'int((nf+1)/2) * W/nf * 0.29'" 
pd="'2*int((nf+1)/2) * (W/nf + 0.29)'"
as="'int((nf+2)/2) * W/nf * 0.29'" 
ps="'2*int((nf+2)/2) * (W/nf + 0.29)'"
nrd="'0.29 / W'" nrs="'0.29 / W'"
sa=0 sb=0 sd=0
model=pfet_01v8
spiceprefix=X
}
C {madvlsi/pmos3.sym} 1460 -300 1 1 {name=M28
L=.6
W=1.5
body=VDD
nf=1
mult=1
ad="'int((nf+1)/2) * W/nf * 0.29'" 
pd="'2*int((nf+1)/2) * (W/nf + 0.29)'"
as="'int((nf+2)/2) * W/nf * 0.29'" 
ps="'2*int((nf+2)/2) * (W/nf + 0.29)'"
nrd="'0.29 / W'" nrs="'0.29 / W'"
sa=0 sb=0 sd=0
model=pfet_01v8
spiceprefix=X
}
C {madvlsi/pmos3.sym} 1580 -200 1 1 {name=M29
L=.6
W=1.5
body=VDD
nf=1
mult=1
ad="'int((nf+1)/2) * W/nf * 0.29'" 
pd="'2*int((nf+1)/2) * (W/nf + 0.29)'"
as="'int((nf+2)/2) * W/nf * 0.29'" 
ps="'2*int((nf+2)/2) * (W/nf + 0.29)'"
nrd="'0.29 / W'" nrs="'0.29 / W'"
sa=0 sb=0 sd=0
model=pfet_01v8
spiceprefix=X
}
C {madvlsi/pmos3.sym} 1580 -300 1 1 {name=MD30
L=.6
W=1.5
body=VDD
nf=1
mult=1
ad="'int((nf+1)/2) * W/nf * 0.29'" 
pd="'2*int((nf+1)/2) * (W/nf + 0.29)'"
as="'int((nf+2)/2) * W/nf * 0.29'" 
ps="'2*int((nf+2)/2) * (W/nf + 0.29)'"
nrd="'0.29 / W'" nrs="'0.29 / W'"
sa=0 sb=0 sd=0
model=pfet_01v8
spiceprefix=X
}
C {madvlsi/pmos3.sym} 1340 -300 1 1 {name=MD31
L=.6
W=1.5
body=VDD
nf=1
mult=1
ad="'int((nf+1)/2) * W/nf * 0.29'" 
pd="'2*int((nf+1)/2) * (W/nf + 0.29)'"
as="'int((nf+2)/2) * W/nf * 0.29'" 
ps="'2*int((nf+2)/2) * (W/nf + 0.29)'"
nrd="'0.29 / W'" nrs="'0.29 / W'"
sa=0 sb=0 sd=0
model=pfet_01v8
spiceprefix=X
}
C {madvlsi/pmos3.sym} 1220 -200 1 1 {name=M32
L=.6
W=1.5
body=VDD
nf=1
mult=1
ad="'int((nf+1)/2) * W/nf * 0.29'" 
pd="'2*int((nf+1)/2) * (W/nf + 0.29)'"
as="'int((nf+2)/2) * W/nf * 0.29'" 
ps="'2*int((nf+2)/2) * (W/nf + 0.29)'"
nrd="'0.29 / W'" nrs="'0.29 / W'"
sa=0 sb=0 sd=0
model=pfet_01v8
spiceprefix=X
}
C {madvlsi/pmos3.sym} 1100 -200 1 1 {name=M33
L=.6
W=1.5
body=VDD
nf=1
mult=1
ad="'int((nf+1)/2) * W/nf * 0.29'" 
pd="'2*int((nf+1)/2) * (W/nf + 0.29)'"
as="'int((nf+2)/2) * W/nf * 0.29'" 
ps="'2*int((nf+2)/2) * (W/nf + 0.29)'"
nrd="'0.29 / W'" nrs="'0.29 / W'"
sa=0 sb=0 sd=0
model=pfet_01v8
spiceprefix=X
}
C {madvlsi/pmos3.sym} 1220 -300 1 1 {name=M34
L=.6
W=1.5
body=VDD
nf=1
mult=1
ad="'int((nf+1)/2) * W/nf * 0.29'" 
pd="'2*int((nf+1)/2) * (W/nf + 0.29)'"
as="'int((nf+2)/2) * W/nf * 0.29'" 
ps="'2*int((nf+2)/2) * (W/nf + 0.29)'"
nrd="'0.29 / W'" nrs="'0.29 / W'"
sa=0 sb=0 sd=0
model=pfet_01v8
spiceprefix=X
}
C {madvlsi/pmos3.sym} 1100 -300 1 1 {name=M35
L=.6
W=1.5
body=VDD
nf=1
mult=1
ad="'int((nf+1)/2) * W/nf * 0.29'" 
pd="'2*int((nf+1)/2) * (W/nf + 0.29)'"
as="'int((nf+2)/2) * W/nf * 0.29'" 
ps="'2*int((nf+2)/2) * (W/nf + 0.29)'"
nrd="'0.29 / W'" nrs="'0.29 / W'"
sa=0 sb=0 sd=0
model=pfet_01v8
spiceprefix=X
}
C {madvlsi/pmos3.sym} 980 -200 1 1 {name=M36
L=.6
W=1.5
body=VDD
nf=1
mult=1
ad="'int((nf+1)/2) * W/nf * 0.29'" 
pd="'2*int((nf+1)/2) * (W/nf + 0.29)'"
as="'int((nf+2)/2) * W/nf * 0.29'" 
ps="'2*int((nf+2)/2) * (W/nf + 0.29)'"
nrd="'0.29 / W'" nrs="'0.29 / W'"
sa=0 sb=0 sd=0
model=pfet_01v8
spiceprefix=X
}
C {madvlsi/pmos3.sym} 860 -200 1 1 {name=M37
L=.6
W=1.5
body=VDD
nf=1
mult=1
ad="'int((nf+1)/2) * W/nf * 0.29'" 
pd="'2*int((nf+1)/2) * (W/nf + 0.29)'"
as="'int((nf+2)/2) * W/nf * 0.29'" 
ps="'2*int((nf+2)/2) * (W/nf + 0.29)'"
nrd="'0.29 / W'" nrs="'0.29 / W'"
sa=0 sb=0 sd=0
model=pfet_01v8
spiceprefix=X
}
C {madvlsi/pmos3.sym} 980 -300 1 1 {name=M38
L=.6
W=1.5
body=VDD
nf=1
mult=1
ad="'int((nf+1)/2) * W/nf * 0.29'" 
pd="'2*int((nf+1)/2) * (W/nf + 0.29)'"
as="'int((nf+2)/2) * W/nf * 0.29'" 
ps="'2*int((nf+2)/2) * (W/nf + 0.29)'"
nrd="'0.29 / W'" nrs="'0.29 / W'"
sa=0 sb=0 sd=0
model=pfet_01v8
spiceprefix=X
}
C {madvlsi/pmos3.sym} 860 -300 1 1 {name=M39
L=.6
W=1.5
body=VDD
nf=1
mult=1
ad="'int((nf+1)/2) * W/nf * 0.29'" 
pd="'2*int((nf+1)/2) * (W/nf + 0.29)'"
as="'int((nf+2)/2) * W/nf * 0.29'" 
ps="'2*int((nf+2)/2) * (W/nf + 0.29)'"
nrd="'0.29 / W'" nrs="'0.29 / W'"
sa=0 sb=0 sd=0
model=pfet_01v8
spiceprefix=X
}
C {madvlsi/nmos3.sym} 1820 180 3 1 {name=M40
L=.6
W=1.5
body=GND
nf=1
mult=1
ad="'int((nf+1)/2) * W/nf * 0.29'" 
pd="'2*int((nf+1)/2) * (W/nf + 0.29)'"
as="'int((nf+2)/2) * W/nf * 0.29'" 
ps="'2*int((nf+2)/2) * (W/nf + 0.29)'"
nrd="'0.29 / W'" nrs="'0.29 / W'"
sa=0 sb=0 sd=0
model=nfet_01v8
spiceprefix=X
}
C {madvlsi/nmos3.sym} 1700 180 3 1 {name=MD41
L=.6
W=1.5
body=GND
nf=1
mult=1
ad="'int((nf+1)/2) * W/nf * 0.29'" 
pd="'2*int((nf+1)/2) * (W/nf + 0.29)'"
as="'int((nf+2)/2) * W/nf * 0.29'" 
ps="'2*int((nf+2)/2) * (W/nf + 0.29)'"
nrd="'0.29 / W'" nrs="'0.29 / W'"
sa=0 sb=0 sd=0
model=nfet_01v8
spiceprefix=X
}
C {madvlsi/nmos3.sym} 1820 80 3 1 {name=M42
L=.6
W=1.5
body=GND
nf=1
mult=1
ad="'int((nf+1)/2) * W/nf * 0.29'" 
pd="'2*int((nf+1)/2) * (W/nf + 0.29)'"
as="'int((nf+2)/2) * W/nf * 0.29'" 
ps="'2*int((nf+2)/2) * (W/nf + 0.29)'"
nrd="'0.29 / W'" nrs="'0.29 / W'"
sa=0 sb=0 sd=0
model=nfet_01v8
spiceprefix=X
}
C {madvlsi/nmos3.sym} 1940 180 3 1 {name=M43
L=.6
W=1.5
body=GND
nf=1
mult=1
ad="'int((nf+1)/2) * W/nf * 0.29'" 
pd="'2*int((nf+1)/2) * (W/nf + 0.29)'"
as="'int((nf+2)/2) * W/nf * 0.29'" 
ps="'2*int((nf+2)/2) * (W/nf + 0.29)'"
nrd="'0.29 / W'" nrs="'0.29 / W'"
sa=0 sb=0 sd=0
model=nfet_01v8
spiceprefix=X
}
C {madvlsi/nmos3.sym} 1940 80 3 1 {name=MD44
L=.6
W=1.5
body=GND
nf=1
mult=1
ad="'int((nf+1)/2) * W/nf * 0.29'" 
pd="'2*int((nf+1)/2) * (W/nf + 0.29)'"
as="'int((nf+2)/2) * W/nf * 0.29'" 
ps="'2*int((nf+2)/2) * (W/nf + 0.29)'"
nrd="'0.29 / W'" nrs="'0.29 / W'"
sa=0 sb=0 sd=0
model=nfet_01v8
spiceprefix=X
}
C {madvlsi/nmos3.sym} 1700 80 3 1 {name=M45
L=.6
W=1.5
body=GND
nf=1
mult=1
ad="'int((nf+1)/2) * W/nf * 0.29'" 
pd="'2*int((nf+1)/2) * (W/nf + 0.29)'"
as="'int((nf+2)/2) * W/nf * 0.29'" 
ps="'2*int((nf+2)/2) * (W/nf + 0.29)'"
nrd="'0.29 / W'" nrs="'0.29 / W'"
sa=0 sb=0 sd=0
model=nfet_01v8
spiceprefix=X
}
C {madvlsi/nmos3.sym} 1460 80 3 1 {name=M46
L=.6
W=1.5
body=GND
nf=1
mult=1
ad="'int((nf+1)/2) * W/nf * 0.29'" 
pd="'2*int((nf+1)/2) * (W/nf + 0.29)'"
as="'int((nf+2)/2) * W/nf * 0.29'" 
ps="'2*int((nf+2)/2) * (W/nf + 0.29)'"
nrd="'0.29 / W'" nrs="'0.29 / W'"
sa=0 sb=0 sd=0
model=nfet_01v8
spiceprefix=X
}
C {madvlsi/nmos3.sym} 1340 80 3 1 {name=MD47
L=.6
W=1.5
body=GND
nf=1
mult=1
ad="'int((nf+1)/2) * W/nf * 0.29'" 
pd="'2*int((nf+1)/2) * (W/nf + 0.29)'"
as="'int((nf+2)/2) * W/nf * 0.29'" 
ps="'2*int((nf+2)/2) * (W/nf + 0.29)'"
nrd="'0.29 / W'" nrs="'0.29 / W'"
sa=0 sb=0 sd=0
model=nfet_01v8
spiceprefix=X
}
C {madvlsi/nmos3.sym} 1460 180 3 1 {name=M48
L=.6
W=1.5
body=GND
nf=1
mult=1
ad="'int((nf+1)/2) * W/nf * 0.29'" 
pd="'2*int((nf+1)/2) * (W/nf + 0.29)'"
as="'int((nf+2)/2) * W/nf * 0.29'" 
ps="'2*int((nf+2)/2) * (W/nf + 0.29)'"
nrd="'0.29 / W'" nrs="'0.29 / W'"
sa=0 sb=0 sd=0
model=nfet_01v8
spiceprefix=X
}
C {madvlsi/nmos3.sym} 1580 80 3 1 {name=M49
L=.6
W=1.5
body=GND
nf=1
mult=1
ad="'int((nf+1)/2) * W/nf * 0.29'" 
pd="'2*int((nf+1)/2) * (W/nf + 0.29)'"
as="'int((nf+2)/2) * W/nf * 0.29'" 
ps="'2*int((nf+2)/2) * (W/nf + 0.29)'"
nrd="'0.29 / W'" nrs="'0.29 / W'"
sa=0 sb=0 sd=0
model=nfet_01v8
spiceprefix=X
}
C {madvlsi/nmos3.sym} 1580 180 3 1 {name=MD50
L=.6
W=1.5
body=GND
nf=1
mult=1
ad="'int((nf+1)/2) * W/nf * 0.29'" 
pd="'2*int((nf+1)/2) * (W/nf + 0.29)'"
as="'int((nf+2)/2) * W/nf * 0.29'" 
ps="'2*int((nf+2)/2) * (W/nf + 0.29)'"
nrd="'0.29 / W'" nrs="'0.29 / W'"
sa=0 sb=0 sd=0
model=nfet_01v8
spiceprefix=X
}
C {madvlsi/nmos3.sym} 1340 180 3 1 {name=MD51
L=.6
W=1.5
body=GND
nf=1
mult=1
ad="'int((nf+1)/2) * W/nf * 0.29'" 
pd="'2*int((nf+1)/2) * (W/nf + 0.29)'"
as="'int((nf+2)/2) * W/nf * 0.29'" 
ps="'2*int((nf+2)/2) * (W/nf + 0.29)'"
nrd="'0.29 / W'" nrs="'0.29 / W'"
sa=0 sb=0 sd=0
model=nfet_01v8
spiceprefix=X
}
C {madvlsi/nmos3.sym} 1100 80 3 1 {name=M52
L=.6
W=1.5
body=GND
nf=1
mult=1
ad="'int((nf+1)/2) * W/nf * 0.29'" 
pd="'2*int((nf+1)/2) * (W/nf + 0.29)'"
as="'int((nf+2)/2) * W/nf * 0.29'" 
ps="'2*int((nf+2)/2) * (W/nf + 0.29)'"
nrd="'0.29 / W'" nrs="'0.29 / W'"
sa=0 sb=0 sd=0
model=nfet_01v8
spiceprefix=X
}
C {madvlsi/nmos3.sym} 980 80 3 1 {name=MD53
L=.6
W=1.5
body=GND
nf=1
mult=1
ad="'int((nf+1)/2) * W/nf * 0.29'" 
pd="'2*int((nf+1)/2) * (W/nf + 0.29)'"
as="'int((nf+2)/2) * W/nf * 0.29'" 
ps="'2*int((nf+2)/2) * (W/nf + 0.29)'"
nrd="'0.29 / W'" nrs="'0.29 / W'"
sa=0 sb=0 sd=0
model=nfet_01v8
spiceprefix=X
}
C {madvlsi/nmos3.sym} 1100 180 3 1 {name=M54
L=.6
W=1.5
body=GND
nf=1
mult=1
ad="'int((nf+1)/2) * W/nf * 0.29'" 
pd="'2*int((nf+1)/2) * (W/nf + 0.29)'"
as="'int((nf+2)/2) * W/nf * 0.29'" 
ps="'2*int((nf+2)/2) * (W/nf + 0.29)'"
nrd="'0.29 / W'" nrs="'0.29 / W'"
sa=0 sb=0 sd=0
model=nfet_01v8
spiceprefix=X
}
C {madvlsi/nmos3.sym} 1220 80 3 1 {name=M55
L=.6
W=1.5
body=GND
nf=1
mult=1
ad="'int((nf+1)/2) * W/nf * 0.29'" 
pd="'2*int((nf+1)/2) * (W/nf + 0.29)'"
as="'int((nf+2)/2) * W/nf * 0.29'" 
ps="'2*int((nf+2)/2) * (W/nf + 0.29)'"
nrd="'0.29 / W'" nrs="'0.29 / W'"
sa=0 sb=0 sd=0
model=nfet_01v8
spiceprefix=X
}
C {madvlsi/nmos3.sym} 1220 180 3 1 {name=M56
L=.6
W=1.5
body=GND
nf=1
mult=1
ad="'int((nf+1)/2) * W/nf * 0.29'" 
pd="'2*int((nf+1)/2) * (W/nf + 0.29)'"
as="'int((nf+2)/2) * W/nf * 0.29'" 
ps="'2*int((nf+2)/2) * (W/nf + 0.29)'"
nrd="'0.29 / W'" nrs="'0.29 / W'"
sa=0 sb=0 sd=0
model=nfet_01v8
spiceprefix=X
}
C {madvlsi/nmos3.sym} 980 180 3 1 {name=MD57
L=.6
W=1.5
body=GND
nf=1
mult=1
ad="'int((nf+1)/2) * W/nf * 0.29'" 
pd="'2*int((nf+1)/2) * (W/nf + 0.29)'"
as="'int((nf+2)/2) * W/nf * 0.29'" 
ps="'2*int((nf+2)/2) * (W/nf + 0.29)'"
nrd="'0.29 / W'" nrs="'0.29 / W'"
sa=0 sb=0 sd=0
model=nfet_01v8
spiceprefix=X
}
C {madvlsi/nmos3.sym} 860 80 3 1 {name=M58
L=.6
W=1.5
body=GND
nf=1
mult=1
ad="'int((nf+1)/2) * W/nf * 0.29'" 
pd="'2*int((nf+1)/2) * (W/nf + 0.29)'"
as="'int((nf+2)/2) * W/nf * 0.29'" 
ps="'2*int((nf+2)/2) * (W/nf + 0.29)'"
nrd="'0.29 / W'" nrs="'0.29 / W'"
sa=0 sb=0 sd=0
model=nfet_01v8
spiceprefix=X
}
C {madvlsi/nmos3.sym} 860 180 3 1 {name=M59
L=.6
W=1.5
body=GND
nf=1
mult=1
ad="'int((nf+1)/2) * W/nf * 0.29'" 
pd="'2*int((nf+1)/2) * (W/nf + 0.29)'"
as="'int((nf+2)/2) * W/nf * 0.29'" 
ps="'2*int((nf+2)/2) * (W/nf + 0.29)'"
nrd="'0.29 / W'" nrs="'0.29 / W'"
sa=0 sb=0 sd=0
model=nfet_01v8
spiceprefix=X
}
C {madvlsi/pmos3.sym} 2060 -300 1 1 {name=M60
L=.6
W=1.5
body=VDD
nf=1
mult=1
ad="'int((nf+1)/2) * W/nf * 0.29'" 
pd="'2*int((nf+1)/2) * (W/nf + 0.29)'"
as="'int((nf+2)/2) * W/nf * 0.29'" 
ps="'2*int((nf+2)/2) * (W/nf + 0.29)'"
nrd="'0.29 / W'" nrs="'0.29 / W'"
sa=0 sb=0 sd=0
model=pfet_01v8
spiceprefix=X
}
C {madvlsi/pmos3.sym} 2060 -200 1 1 {name=M61
L=.6
W=1.5
body=VDD
nf=1
mult=1
ad="'int((nf+1)/2) * W/nf * 0.29'" 
pd="'2*int((nf+1)/2) * (W/nf + 0.29)'"
as="'int((nf+2)/2) * W/nf * 0.29'" 
ps="'2*int((nf+2)/2) * (W/nf + 0.29)'"
nrd="'0.29 / W'" nrs="'0.29 / W'"
sa=0 sb=0 sd=0
model=pfet_01v8
spiceprefix=X
}
C {madvlsi/nmos3.sym} 2060 180 3 1 {name=M62
L=.6
W=1.5
body=GND
nf=1
mult=1
ad="'int((nf+1)/2) * W/nf * 0.29'" 
pd="'2*int((nf+1)/2) * (W/nf + 0.29)'"
as="'int((nf+2)/2) * W/nf * 0.29'" 
ps="'2*int((nf+2)/2) * (W/nf + 0.29)'"
nrd="'0.29 / W'" nrs="'0.29 / W'"
sa=0 sb=0 sd=0
model=nfet_01v8
spiceprefix=X
}
C {madvlsi/nmos3.sym} 2060 80 3 1 {name=M63
L=.6
W=1.5
body=GND
nf=1
mult=1
ad="'int((nf+1)/2) * W/nf * 0.29'" 
pd="'2*int((nf+1)/2) * (W/nf + 0.29)'"
as="'int((nf+2)/2) * W/nf * 0.29'" 
ps="'2*int((nf+2)/2) * (W/nf + 0.29)'"
nrd="'0.29 / W'" nrs="'0.29 / W'"
sa=0 sb=0 sd=0
model=nfet_01v8
spiceprefix=X
}
C {madvlsi/nmos3.sym} 2160 180 3 1 {name=MD64
L=.6
W=1.5
body=GND
nf=1
mult=1
ad="'int((nf+1)/2) * W/nf * 0.29'" 
pd="'2*int((nf+1)/2) * (W/nf + 0.29)'"
as="'int((nf+2)/2) * W/nf * 0.29'" 
ps="'2*int((nf+2)/2) * (W/nf + 0.29)'"
nrd="'0.29 / W'" nrs="'0.29 / W'"
sa=0 sb=0 sd=0
model=nfet_01v8
spiceprefix=X
}
C {madvlsi/nmos3.sym} 2160 80 3 1 {name=MD65
L=.6
W=1.5
body=GND
nf=1
mult=1
ad="'int((nf+1)/2) * W/nf * 0.29'" 
pd="'2*int((nf+1)/2) * (W/nf + 0.29)'"
as="'int((nf+2)/2) * W/nf * 0.29'" 
ps="'2*int((nf+2)/2) * (W/nf + 0.29)'"
nrd="'0.29 / W'" nrs="'0.29 / W'"
sa=0 sb=0 sd=0
model=nfet_01v8
spiceprefix=X
}
C {madvlsi/pmos3.sym} 2180 -300 1 1 {name=MD66
L=.6
W=1.5
body=VDD
nf=1
mult=1
ad="'int((nf+1)/2) * W/nf * 0.29'" 
pd="'2*int((nf+1)/2) * (W/nf + 0.29)'"
as="'int((nf+2)/2) * W/nf * 0.29'" 
ps="'2*int((nf+2)/2) * (W/nf + 0.29)'"
nrd="'0.29 / W'" nrs="'0.29 / W'"
sa=0 sb=0 sd=0
model=pfet_01v8
spiceprefix=X
}
C {madvlsi/pmos3.sym} 2180 -200 1 1 {name=MD67
L=.6
W=1.5
body=VDD
nf=1
mult=1
ad="'int((nf+1)/2) * W/nf * 0.29'" 
pd="'2*int((nf+1)/2) * (W/nf + 0.29)'"
as="'int((nf+2)/2) * W/nf * 0.29'" 
ps="'2*int((nf+2)/2) * (W/nf + 0.29)'"
nrd="'0.29 / W'" nrs="'0.29 / W'"
sa=0 sb=0 sd=0
model=pfet_01v8
spiceprefix=X
}
